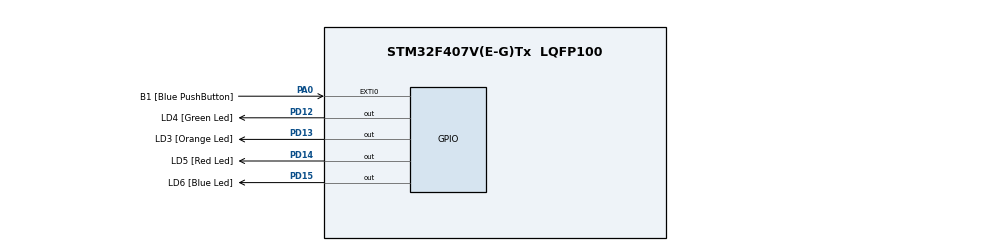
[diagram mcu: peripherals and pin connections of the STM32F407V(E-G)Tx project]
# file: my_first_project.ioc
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Mcu.Family=STM32F4
Mcu.Name=STM32F407V(E-G)Tx
Mcu.Package=LQFP100
NVIC.PriorityGroup=NVIC_PRIORITYGROUP_0
PA0-WKUP.GPIO_Label=B1 [Blue PushButton]
PA0-WKUP.GPIO_ModeDefaultEXTI=GPIO_MODE_EVT_RISING
PA0-WKUP.GPIO_PuPd=GPIO_NOPULL
PA0-WKUP.Signal=GPXTI0
PA13.Mode=Trace_Asynchronous_SW
PA13.Signal=SYS_JTMS-SWDIO
PA14.Mode=Trace_Asynchronous_SW
PA14.Signal=SYS_JTCK-SWCLK
PB3.Mode=Trace_Asynchronous_SW
PB3.Signal=SYS_JTDO-SWO
PD12.GPIO_Label=LD4 [Green Led]
PD12.GPIO_PuPd=GPIO_NOPULL
PD12.GPIO_Speed=GPIO_SPEED_FREQ_LOW
PD12.Signal=GPIO_Output
PD13.GPIO_Label=LD3 [Orange Led]
PD13.GPIO_PuPd=GPIO_NOPULL
PD13.GPIO_Speed=GPIO_SPEED_FREQ_LOW
PD13.Signal=GPIO_Output
PD14.GPIO_Label=LD5 [Red Led]
PD14.GPIO_PuPd=GPIO_NOPULL
PD14.GPIO_Speed=GPIO_SPEED_FREQ_LOW
PD14.Signal=GPIO_Output
PD15.GPIO_Label=LD6 [Blue Led]
PD15.GPIO_PuPd=GPIO_NOPULL
PD15.GPIO_Speed=GPIO_SPEED_FREQ_LOW
PD15.Signal=GPIO_Output
ProjectManager.HeapSize=0x200
ProjectManager.StackSize=0x400
ProjectManager.TargetToolchain=Makefile
RCC.48MHZClocksFreq_Value=28571428.57142857
RCC.AHBFreq_Value=16000000
RCC.APB1CLKDivider=RCC_HCLK_DIV4
RCC.APB1Freq_Value=4000000
RCC.APB1TimFreq_Value=8000000
RCC.APB2CLKDivider=RCC_HCLK_DIV2
RCC.APB2Freq_Value=8000000
RCC.APB2TimFreq_Value=16000000
RCC.CortexFreq_Value=16000000
RCC.HCLKFreq_Value=16000000
RCC.HSE_VALUE=8000000
RCC.HSI_VALUE=16000000
RCC.LSE_VALUE=32768
RCC.PLLM=8
RCC.PLLN=100
RCC.PLLQ=7
RCC.SYSCLKFreq_VALUE=16000000
RCC.VCOOutputFreq_Value=200000000
board=STM32F407G-DISC1

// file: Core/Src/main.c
/* USER CODE BEGIN Header */
/**
  ******************************************************************************
  * @file           : main.c
  * @brief          : Main program body
  ******************************************************************************
  * @attention
  *
  * Copyright (c) 2024 STMicroelectronics.
  * All rights reserved.
  *
  * This software is licensed under terms that can be found in the LICENSE file
  * in the root directory of this software component.
  * If no LICENSE file comes with this software, it is provided AS-IS.
  *
  ******************************************************************************
  */
/* USER CODE END Header */
#include "main.h"

TaskHandle_t task1_handle = NULL;
/* USER CODE BEGIN PV */
uint8_t toggle = 0;
uint8_t gpio_event_flag = 0;
volatile uint8_t input_status = 0;

BaseType_t status;
/* USER CODE END PV */

void SystemClock_Config(void);
static void MX_GPIO_Init(void);
static void MX_Interrupt_Init(void);

static void task_1(void *task_entry);

int main(void)
{

  /* MCU Configuration--------------------------------------------------------*/

  /* Reset of all peripherals, Initializes the Flash interface and the Systick. */
  HAL_Init();

  /* Configure the system clock */
  SystemClock_Config();

  /* Initialize all configured peripherals */
  MX_GPIO_Init();
  MX_Interrupt_Init();
  /* USER CODE BEGIN 2 */

  /* definition and creation of defaultTask */
  status = xTaskCreate(task_1, "task_1", 1024, NULL, 4, &task1_handle);
  if(status != pdPASS) {
    Error_Handler();
  }
  vTaskStartScheduler();

  /* USER CODE END 2 */

  /* Infinite loop */
  while (1)
  {

  }
}

static void task_1(void *task_entry)
{
  while (1) {
    input_status = HAL_GPIO_ReadPin(B1_GPIO_Port, B1_Pin);
    if (gpio_event_flag == 1) {
      gpio_event_flag = 0;
      toggle ^= 1;
      HAL_GPIO_WritePin(LD4_GPIO_Port, LD4_Pin, toggle);
      vTaskDelay(250);
      HAL_GPIO_WritePin(LD3_GPIO_Port, LD3_Pin, toggle);
      vTaskDelay(250);
      HAL_GPIO_WritePin(LD5_GPIO_Port, LD5_Pin, toggle);
      vTaskDelay(250);
      HAL_GPIO_WritePin(LD6_GPIO_Port, LD6_Pin, toggle);
      vTaskDelay(250);
    }
  }
}

void SystemClock_Config(void)
{
  RCC_OscInitTypeDef RCC_OscInitStruct = {0};
  RCC_ClkInitTypeDef RCC_ClkInitStruct = {0};

  /** Configure the main internal regulator output voltage
  */
  __HAL_RCC_PWR_CLK_ENABLE();
  __HAL_PWR_VOLTAGESCALING_CONFIG(PWR_REGULATOR_VOLTAGE_SCALE1);

  /** Initializes the RCC Oscillators according to the specified parameters
  * in the RCC_OscInitTypeDef structure.
  */
  RCC_OscInitStruct.OscillatorType = RCC_OSCILLATORTYPE_HSE;
  RCC_OscInitStruct.HSEState = RCC_HSE_ON;
  RCC_OscInitStruct.PLL.PLLState = RCC_PLL_ON;
  RCC_OscInitStruct.PLL.PLLSource = RCC_PLLSOURCE_HSE;
  RCC_OscInitStruct.PLL.PLLM = 8;
  RCC_OscInitStruct.PLL.PLLN = 336;
  RCC_OscInitStruct.PLL.PLLP = RCC_PLLP_DIV2;
  RCC_OscInitStruct.PLL.PLLQ = 7;
  if (HAL_RCC_OscConfig(&RCC_OscInitStruct) != HAL_OK)
  {
    Error_Handler();
  }

  /** Initializes the CPU, AHB and APB buses clocks
  */
  RCC_ClkInitStruct.ClockType = RCC_CLOCKTYPE_HCLK|RCC_CLOCKTYPE_SYSCLK
                              |RCC_CLOCKTYPE_PCLK1|RCC_CLOCKTYPE_PCLK2;
  RCC_ClkInitStruct.SYSCLKSource = RCC_SYSCLKSOURCE_PLLCLK;
  RCC_ClkInitStruct.AHBCLKDivider = RCC_SYSCLK_DIV1;
  RCC_ClkInitStruct.APB1CLKDivider = RCC_HCLK_DIV4;
  RCC_ClkInitStruct.APB2CLKDivider = RCC_HCLK_DIV2;

  if (HAL_RCC_ClockConfig(&RCC_ClkInitStruct, FLASH_LATENCY_5) != HAL_OK)
  {
    Error_Handler();
  }
}

static void MX_GPIO_Init(void)
{
  GPIO_InitTypeDef GPIO_InitStruct = {0};

  /* GPIO Ports Clock Enable */
  __HAL_RCC_GPIOA_CLK_ENABLE();
  __HAL_RCC_GPIOD_CLK_ENABLE();
  __HAL_RCC_GPIOB_CLK_ENABLE();

  /*Configure GPIO pin Output Level */
  HAL_GPIO_WritePin(GPIOD, LD4_Pin|LD3_Pin|LD5_Pin|LD6_Pin, GPIO_PIN_RESET);

  /*Configure GPIO pin : B1_Pin */
  GPIO_InitStruct.Pin = B1_Pin;
  GPIO_InitStruct.Mode = GPIO_MODE_IT_FALLING;
  GPIO_InitStruct.Pull = GPIO_PULLDOWN;
  HAL_GPIO_Init(B1_GPIO_Port, &GPIO_InitStruct);

  /*Configure GPIO pins : LD4_Pin LD3_Pin LD5_Pin LD6_Pin */
  GPIO_InitStruct.Pin = LD4_Pin|LD3_Pin|LD5_Pin|LD6_Pin;
  GPIO_InitStruct.Mode = GPIO_MODE_OUTPUT_PP;
  GPIO_InitStruct.Pull = GPIO_NOPULL;
  GPIO_InitStruct.Speed = GPIO_SPEED_FREQ_LOW;
  HAL_GPIO_Init(GPIOD, &GPIO_InitStruct);

}

static void MX_Interrupt_Init(void)
{

  HAL_NVIC_SetPriority(EXTI0_IRQn, 5, 5);
  HAL_NVIC_EnableIRQ(EXTI0_IRQn);

}

void HAL_TIM_PeriodElapsedCallback(TIM_HandleTypeDef *htim)
{
  if (htim->Instance == TIM6)
  {
    HAL_IncTick();
  }
}

void Error_Handler(void)
{
  __disable_irq();
  while (1)
  {
  }
}

/**
  * @brief  EXTI line detection callbacks.
  * @param  GPIO_Pin Specifies the pins connected EXTI line
  * @retval None
  */
void HAL_GPIO_EXTI_Callback(uint16_t GPIO_Pin)
{
  if (GPIO_Pin == GPIO_PIN_0) {
    if(HAL_GPIO_ReadPin(B1_GPIO_Port, B1_Pin) == GPIO_PIN_SET) {
      gpio_event_flag = 1;
    }
  }
}
